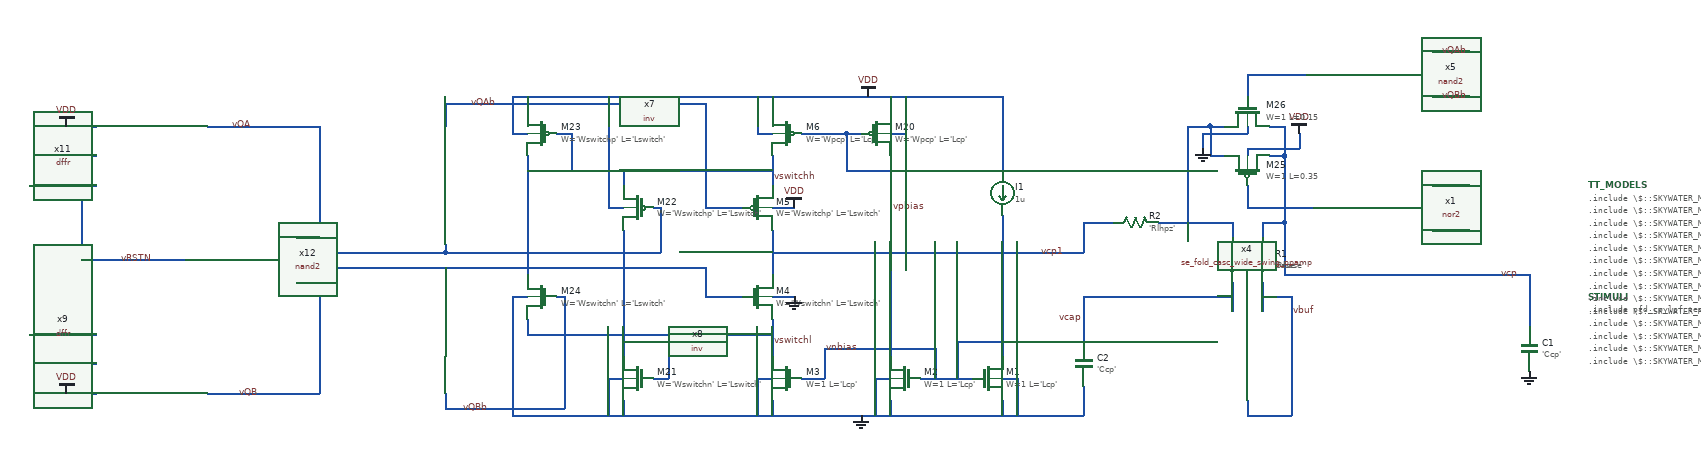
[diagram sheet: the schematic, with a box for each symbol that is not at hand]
v {xschem version=2.9.9 file_version=1.2 }
G {}
K {}
V {}
S {}
E {}
N -160 -350 -70 -350 { lab=vin_div}
N -160 -550 -70 -550 { lab=vsig_in}
N 200 -420 230 -420 { lab=vQB}
N 1000 -260 1000 -240 { lab=GND}
N 980 -290 1000 -290 { lab=GND}
N 980 -290 980 -240 { lab=GND}
N 1000 -620 1020 -620 { lab=VDD}
N 1000 -670 1000 -650 { lab=VDD}
N 1020 -670 1020 -620 { lab=VDD}
N 1040 -290 1110 -290 { lab=vnbias}
N 940 -620 940 -570 { lab=vpbias}
N 940 -570 1000 -570 { lab=vpbias}
N 940 -620 960 -620 { lab=vpbias}
N 1000 -590 1000 -320 { lab=vpbias}
N 1150 -260 1150 -240 { lab=GND}
N 1150 -290 1170 -290 { lab=GND}
N 1170 -290 1170 -240 { lab=GND}
N 880 -620 940 -620 { lab=vpbias}
N 820 -620 840 -620 { lab=VDD}
N 820 -670 820 -620 { lab=VDD}
N 840 -670 840 -650 { lab=VDD}
N 840 -260 840 -240 { lab=GND}
N 820 -290 840 -290 { lab=GND}
N 820 -290 820 -240 { lab=GND}
N 1060 -330 1060 -290 { lab=vnbias}
N 910 -330 1060 -330 { lab=vnbias}
N 910 -330 910 -290 { lab=vnbias}
N 880 -290 910 -290 { lab=vnbias}
N 840 -590 840 -550 { lab=vswitchh}
N 840 -490 840 -430 { lab=vcp1}
N 840 -370 840 -320 { lab=vswitchl}
N 840 -400 870 -400 { lab=GND}
N 840 -520 870 -520 { lab=VDD}
N 1150 -670 1150 -570 { lab=VDD}
N 1150 -510 1150 -320 { lab=vnbias}
N 1090 -340 1090 -290 { lab=vnbias}
N 1090 -340 1150 -340 { lab=vnbias}
N 1480 -240 1540 -240 { lab=vbuf}
N 1480 -260 1480 -240 { lab=vbuf}
N 1260 -280 1260 -240 { lab=GND}
N 1500 -400 1540 -400 { lab=vbuf}
N 1540 -400 1540 -240 { lab=vbuf}
N 1260 -400 1260 -340 { lab=vcap}
N 1460 -420 1460 -380 { lab=vcap}
N 1500 -420 1500 -380 { lab=vbuf}
N 840 -460 1260 -460 { lab=vcp1}
N 1460 -500 1460 -480 { lab=#net1}
N 1500 -500 1500 -480 { lab=vcp}
N 620 -520 640 -520 { lab=VDD}
N 680 -290 700 -290 { lab=#net2}
N 700 -340 700 -290 { lab=#net2}
N 640 -340 700 -340 { lab=#net2}
N 510 -370 510 -350 { lab=vswitchl}
N 490 -400 510 -400 { lab=GND}
N 490 -620 510 -620 { lab=VDD}
N 490 -670 490 -620 { lab=VDD}
N 510 -670 510 -650 { lab=VDD}
N 620 -290 640 -290 { lab=GND}
N 640 -260 640 -240 { lab=GND}
N 620 -290 620 -240 { lab=GND}
N 550 -620 570 -620 { lab=#net3}
N 570 -620 570 -570 { lab=#net3}
N 510 -570 570 -570 { lab=#net3}
N 640 -570 840 -570 { lab=vswitchh}
N 510 -350 840 -350 { lab=vswitchl}
N 780 -520 800 -520 { lab=vQAb}
N 680 -520 690 -520 { lab=vQA}
N 780 -400 800 -400 { lab=vQB}
N 550 -400 560 -400 { lab=vQBb}
N 490 -240 1260 -240 { lab=GND}
N 490 -670 1150 -670 { lab=VDD}
N 750 -520 780 -520 { lab=vQAb}
N 750 -440 750 -400 { lab=vQB}
N 750 -400 780 -400 { lab=vQB}
N 640 -570 640 -550 { lab=vswitchh}
N 640 -490 640 -320 { lab=#net2}
N 620 -670 620 -520 { lab=VDD}
N 490 -400 490 -240 { lab=GND}
N 510 -590 510 -430 { lab=#net3}
N 1260 -400 1290 -400 { lab=vcap}
N 1430 -630 1430 -610 { lab=#net1}
N 1430 -630 1450 -630 { lab=#net1}
N 1430 -610 1430 -590 { lab=#net1}
N 1430 -590 1450 -590 { lab=#net1}
N 1510 -630 1530 -630 { lab=vcp}
N 1530 -630 1530 -590 { lab=vcp}
N 1510 -590 1530 -590 { lab=vcp}
N 1390 -400 1460 -400 { lab=vcap}
N 1480 -550 1480 -520 { lab=#net4}
N 1480 -700 1480 -670 { lab=#net5}
N 1480 -600 1480 -590 { lab=VDD}
N 1480 -630 1480 -620 { lab=GND}
N 1480 -600 1550 -600 { lab=VDD}
N 1550 -620 1550 -600 { lab=VDD}
N 1420 -620 1480 -620 { lab=GND}
N 1420 -620 1420 -600 { lab=GND}
N 1400 -630 1430 -630 { lab=#net1}
N 1290 -400 1390 -400 { lab=vcap}
N 1260 -500 1260 -460 { lab=vcp1}
N 1500 -500 1530 -500 { lab=vcp}
N 1480 -700 1560 -700 { lab=#net5}
N 1730 -730 1780 -730 { lab=vQAb}
N 1730 -670 1780 -670 { lab=vQBb}
N 1730 -550 1780 -550 { lab=vQA}
N 1730 -490 1780 -490 { lab=vQB}
N 1530 -500 1530 -430 { lab=vcp}
N 1530 -430 1860 -430 { lab=vcp}
N 80 -630 230 -630 { lab=vQA}
N 80 -270 230 -270 { lab=vQB}
N -90 -450 50 -450 { lab=vRSTN}
N 400 -660 400 -630 { lab=vQAb}
N 400 -270 400 -250 { lab=vQBb}
N 400 -470 400 -460 { lab=vQA}
N 400 -440 400 -430 { lab=vQB}
N 230 -630 230 -460 { lab=vQA}
N 230 -460 400 -460 { lab=vQA}
N 400 -660 750 -660 { lab=vQAb}
N 750 -660 750 -520 { lab=vQAb}
N 400 -460 690 -460 { lab=vQA}
N 690 -520 690 -460 { lab=vQA}
N 200 -480 230 -480 { lab=vQA}
N 230 -440 230 -420 { lab=vQB}
N 230 -440 750 -440 { lab=vQB}
N 400 -250 560 -250 { lab=vQBb}
N 560 -400 560 -250 { lab=vQBb}
N -90 -310 -70 -310 { lab=vRSTN}
N -90 -590 -90 -310 { lab=vRSTN}
N -90 -590 -70 -590 { lab=vRSTN}
N -110 -630 -70 -630 { lab=VDD}
N -110 -270 -70 -270 { lab=VDD}
N 1860 -430 1860 -360 { lab=vcp}
N 1260 -500 1300 -500 { lab=vcp1}
N 1360 -500 1460 -500 { lab=#net1}
N 1400 -630 1400 -500 { lab=#net1}
N 1530 -590 1530 -500 { lab=vcp}
N 1480 -520 1570 -520 { lab=#net4}
N 230 -420 230 -270 { lab=vQB}
C {devices/title.sym} 160 -30 0 0 {name=l1 author="Nikhil Poole"}
C {devices/code.sym} 1940 -400 0 0 {name=STIMULI 
only_toplevel=true
place=end
value=".include pfd_cp_lpf_test_commands.spice"}
C {devices/code.sym} 1940 -550 0 0 {name=TT_MODELS
only_toplevel=true
format="tcleval( @value )"
value="
.include \\\\$::SKYWATER_MODELS\\\\/cells/nfet_01v8/sky130_fd_pr__nfet_01v8__tt.corner.spice
.include \\\\$::SKYWATER_MODELS\\\\/cells/nfet_01v8_lvt/sky130_fd_pr__nfet_01v8_lvt__tt.corner.spice
.include \\\\$::SKYWATER_MODELS\\\\/cells/pfet_01v8/sky130_fd_pr__pfet_01v8__tt.corner.spice
.include \\\\$::SKYWATER_MODELS\\\\/cells/nfet_03v3_nvt/sky130_fd_pr__nfet_03v3_nvt__tt.corner.spice
.include \\\\$::SKYWATER_MODELS\\\\/cells/nfet_05v0_nvt/sky130_fd_pr__nfet_05v0_nvt__tt.corner.spice
.include \\\\$::SKYWATER_MODELS\\\\/cells/esd_nfet_01v8/sky130_fd_pr__esd_nfet_01v8__tt.corner.spice
.include \\\\$::SKYWATER_MODELS\\\\/cells/pfet_01v8_lvt/sky130_fd_pr__pfet_01v8_lvt__tt.corner.spice
.include \\\\$::SKYWATER_MODELS\\\\/cells/pfet_01v8_hvt/sky130_fd_pr__pfet_01v8_hvt__tt.corner.spice
.include \\\\$::SKYWATER_MODELS\\\\/cells/esd_pfet_g5v0d10v5/sky130_fd_pr__esd_pfet_g5v0d10v5__tt.corner.spice
.include \\\\$::SKYWATER_MODELS\\\\/cells/pfet_g5v0d10v5/sky130_fd_pr__pfet_g5v0d10v5__tt.corner.spice
.include \\\\$::SKYWATER_MODELS\\\\/cells/pfet_g5v0d16v0/sky130_fd_pr__pfet_g5v0d16v0__tt.corner.spice
.include \\\\$::SKYWATER_MODELS\\\\/cells/nfet_g5v0d10v5/sky130_fd_pr__nfet_g5v0d10v5__tt.corner.spice
.include \\\\$::SKYWATER_MODELS\\\\/cells/nfet_g5v0d16v0/sky130_fd_pr__nfet_g5v0d16v0__tt_discrete.corner.spice
.include \\\\$::SKYWATER_MODELS\\\\/cells/esd_nfet_g5v0d10v5/sky130_fd_pr__esd_nfet_g5v0d10v5__tt.corner.spice
.include \\\\$::SKYWATER_MODELS\\\\/models/corners/tt/nonfet.spice
* Mismatch parameters
.include \\\\$::SKYWATER_MODELS\\\\/cells/nfet_01v8/sky130_fd_pr__nfet_01v8__mismatch.corner.spice
.include \\\\$::SKYWATER_MODELS\\\\/cells/pfet_01v8/sky130_fd_pr__pfet_01v8__mismatch.corner.spice
.include \\\\$::SKYWATER_MODELS\\\\/cells/nfet_01v8_lvt/sky130_fd_pr__nfet_01v8_lvt__mismatch.corner.spice
.include \\\\$::SKYWATER_MODELS\\\\/cells/pfet_01v8_lvt/sky130_fd_pr__pfet_01v8_lvt__mismatch.corner.spice
.include \\\\$::SKYWATER_MODELS\\\\/cells/pfet_01v8_hvt/sky130_fd_pr__pfet_01v8_hvt__mismatch.corner.spice
.include \\\\$::SKYWATER_MODELS\\\\/cells/nfet_g5v0d10v5/sky130_fd_pr__nfet_g5v0d10v5__mismatch.corner.spice
.include \\\\$::SKYWATER_MODELS\\\\/cells/pfet_g5v0d10v5/sky130_fd_pr__pfet_g5v0d10v5__mismatch.corner.spice
.include \\\\$::SKYWATER_MODELS\\\\/cells/nfet_05v0_nvt/sky130_fd_pr__nfet_05v0_nvt__mismatch.corner.spice
.include \\\\$::SKYWATER_MODELS\\\\/cells/nfet_03v3_nvt/sky130_fd_pr__nfet_03v3_nvt__mismatch.corner.spice
* Resistor\\\\$::SKYWATER_MODELS\\\\/Capacitor
.include \\\\$::SKYWATER_MODELS\\\\/models/r+c/res_typical__cap_typical.spice
.include \\\\$::SKYWATER_MODELS\\\\/models/r+c/res_typical__cap_typical__lin.spice
* Special cells
.include \\\\$::SKYWATER_MODELS\\\\/models/corners/tt/specialized_cells.spice
* All models
.include \\\\$::SKYWATER_MODELS\\\\/models/all.spice
* Corner
.include \\\\$::SKYWATER_MODELS\\\\/models/corners/tt/rf.spice
"}
C {devices/lab_wire.sym} -100 -550 0 0 {name=l2 sig_type=std_logic lab=vsig_in}
C {devices/lab_wire.sym} -100 -350 0 0 {name=l3 sig_type=std_logic lab=vin_div}
C {devices/lab_wire.sym} 910 -330 0 1 {name=l5 sig_type=std_logic lab=vnbias}
C {devices/lab_wire.sym} 1000 -520 0 1 {name=l6 sig_type=std_logic lab=vpbias}
C {devices/isource.sym} 1150 -540 0 1 {name=I1 value=1u}
C {sky130_fd_pr/nfet_01v8.sym} 1130 -290 0 0 {name=M1
L='Lcp'
W=1
nf=1 
mult=100
ad="'int((nf+1)/2) * W/nf * 0.29'" 
pd="'2*int((nf+1)/2) * (W/nf + 0.29)'"
as="'int((nf+2)/2) * W/nf * 0.29'" 
ps="'2*int((nf+2)/2) * (W/nf + 0.29)'"
nrd="'0.29 / W'" nrs="'0.29 / W'"
sa=0 sb=0 sd=0
model=nfet_01v8
spiceprefix=X
}
C {sky130_fd_pr/nfet_01v8.sym} 1020 -290 0 1 {name=M2
L='Lcp'
W=1
nf=1 
mult=1
ad="'int((nf+1)/2) * W/nf * 0.29'" 
pd="'2*int((nf+1)/2) * (W/nf + 0.29)'"
as="'int((nf+2)/2) * W/nf * 0.29'" 
ps="'2*int((nf+2)/2) * (W/nf + 0.29)'"
nrd="'0.29 / W'" nrs="'0.29 / W'"
sa=0 sb=0 sd=0
model=nfet_01v8
spiceprefix=X
}
C {sky130_fd_pr/nfet_01v8.sym} 860 -290 0 1 {name=M3
L='Lcp'
W=1
nf=1 
mult=1
ad="'int((nf+1)/2) * W/nf * 0.29'" 
pd="'2*int((nf+1)/2) * (W/nf + 0.29)'"
as="'int((nf+2)/2) * W/nf * 0.29'" 
ps="'2*int((nf+2)/2) * (W/nf + 0.29)'"
nrd="'0.29 / W'" nrs="'0.29 / W'"
sa=0 sb=0 sd=0
model=nfet_01v8
spiceprefix=X
}
C {sky130_fd_pr/nfet_01v8_lvt.sym} 820 -400 0 0 {name=M4
L='Lswitch'
W='Wswitchn'
nf=1
mult=1
ad="'int((nf+1)/2) * W/nf * 0.29'" 
pd="'2*int((nf+1)/2) * (W/nf + 0.29)'"
as="'int((nf+2)/2) * W/nf * 0.29'" 
ps="'2*int((nf+2)/2) * (W/nf + 0.29)'"
nrd="'0.29 / W'" nrs="'0.29 / W'"
sa=0 sb=0 sd=0
model=nfet_01v8_lvt
spiceprefix=X
}
C {sky130_fd_pr/pfet_01v8_lvt.sym} 820 -520 0 0 {name=M5
L='Lswitch'
W='Wswitchp'
nf=1
mult=1
ad="'int((nf+1)/2) * W/nf * 0.29'" 
pd="'2*int((nf+1)/2) * (W/nf + 0.29)'"
as="'int((nf+2)/2) * W/nf * 0.29'" 
ps="'2*int((nf+2)/2) * (W/nf + 0.29)'"
nrd="'0.29 / W'" nrs="'0.29 / W'"
sa=0 sb=0 sd=0
model=pfet_01v8_lvt
spiceprefix=X
}
C {devices/gnd.sym} 870 -400 0 0 {name=l7 lab=GND}
C {devices/gnd.sym} 960 -240 0 0 {name=l8 lab=GND}
C {devices/vdd.sym} 970 -670 0 0 {name=l9 lab=VDD}
C {devices/vdd.sym} 870 -520 0 0 {name=l10 lab=VDD}
C {devices/lab_wire.sym} 1820 -430 0 1 {name=l12 sig_type=std_logic lab=vcp}
C {sky130_fd_pr/pfet_01v8.sym} 860 -620 0 1 {name=M6
L='Lcp'
W='Wpcp'
nf=1
mult='Mpcp'
ad="'int((nf+1)/2) * W/nf * 0.29'" 
pd="'2*int((nf+1)/2) * (W/nf + 0.29)'"
as="'int((nf+2)/2) * W/nf * 0.29'" 
ps="'2*int((nf+2)/2) * (W/nf + 0.29)'"
nrd="'0.29 / W'" nrs="'0.29 / W'"
sa=0 sb=0 sd=0
model=pfet_01v8
spiceprefix=X
}
C {sky130_fd_pr/pfet_01v8.sym} 980 -620 0 0 {name=M20
L='Lcp'
W='Wpcp'
nf=1
mult='Mpcp'
ad="'int((nf+1)/2) * W/nf * 0.29'" 
pd="'2*int((nf+1)/2) * (W/nf + 0.29)'"
as="'int((nf+2)/2) * W/nf * 0.29'" 
ps="'2*int((nf+2)/2) * (W/nf + 0.29)'"
nrd="'0.29 / W'" nrs="'0.29 / W'"
sa=0 sb=0 sd=0
model=pfet_01v8
spiceprefix=X
}
C {devices/capa.sym} 1260 -310 0 0 {name=C2
m=1
value='Ccp'
footprint=1206
device="ceramic capacitor"}
C {devices/res.sym} 1500 -450 0 0 {name=R1
value='Rbase'
footprint=1206
device=resistor
m=1}
C {devices/res.sym} 1460 -450 0 1 {name=R4
value='Kcap*Rbase'
footprint=1206
device=resistor
m=1}
C {devices/lab_wire.sym} 1260 -370 0 0 {name=l35 sig_type=std_logic lab=vcap}
C {devices/lab_wire.sym} 1540 -380 2 0 {name=l36 sig_type=std_logic lab=vbuf}
C {/home/users/nhpoole/ee272b/ee272b_mixed_signal_mmwave_accelerator/designs/se_fold_casc_wide_swing_opamp.sym} 1480 -330 3 1 {name=x4}
C {devices/lab_wire.sym} 150 -270 0 0 {name=l37 sig_type=std_logic lab=vQB}
C {devices/lab_wire.sym} 840 -560 0 1 {name=l38 sig_type=std_logic lab=vswitchh}
C {devices/lab_wire.sym} 840 -340 0 1 {name=l39 sig_type=std_logic lab=vswitchl}
C {sky130_fd_pr/nfet_01v8.sym} 660 -290 0 1 {name=M21
L='Lswitch'
W='Wswitchn'
nf=1 
mult=1
ad="'int((nf+1)/2) * W/nf * 0.29'" 
pd="'2*int((nf+1)/2) * (W/nf + 0.29)'"
as="'int((nf+2)/2) * W/nf * 0.29'" 
ps="'2*int((nf+2)/2) * (W/nf + 0.29)'"
nrd="'0.29 / W'" nrs="'0.29 / W'"
sa=0 sb=0 sd=0
model=nfet_01v8
spiceprefix=X
}
C {sky130_fd_pr/pfet_01v8.sym} 660 -520 0 1 {name=M22
L='Lswitch'
W='Wswitchp'
nf=1
mult=1
ad="'int((nf+1)/2) * W/nf * 0.29'" 
pd="'2*int((nf+1)/2) * (W/nf + 0.29)'"
as="'int((nf+2)/2) * W/nf * 0.29'" 
ps="'2*int((nf+2)/2) * (W/nf + 0.29)'"
nrd="'0.29 / W'" nrs="'0.29 / W'"
sa=0 sb=0 sd=0
model=pfet_01v8
spiceprefix=X
}
C {devices/lab_wire.sym} 110 -630 0 1 {name=l40 sig_type=std_logic lab=vQA}
C {sky130_fd_pr/pfet_01v8.sym} 530 -620 0 1 {name=M23
L='Lswitch'
W='Wswitchp'
nf=1
mult=1
ad="'int((nf+1)/2) * W/nf * 0.29'" 
pd="'2*int((nf+1)/2) * (W/nf + 0.29)'"
as="'int((nf+2)/2) * W/nf * 0.29'" 
ps="'2*int((nf+2)/2) * (W/nf + 0.29)'"
nrd="'0.29 / W'" nrs="'0.29 / W'"
sa=0 sb=0 sd=0
model=pfet_01v8
spiceprefix=X
}
C {sky130_fd_pr/nfet_01v8.sym} 530 -400 0 1 {name=M24
L='Lswitch'
W='Wswitchn'
nf=1 
mult=1
ad="'int((nf+1)/2) * W/nf * 0.29'" 
pd="'2*int((nf+1)/2) * (W/nf + 0.29)'"
as="'int((nf+2)/2) * W/nf * 0.29'" 
ps="'2*int((nf+2)/2) * (W/nf + 0.29)'"
nrd="'0.29 / W'" nrs="'0.29 / W'"
sa=0 sb=0 sd=0
model=nfet_01v8
spiceprefix=X
}
C {devices/lab_wire.sym} 460 -250 0 0 {name=l41 sig_type=std_logic lab=vQBb}
C {devices/vdd.sym} 1550 -620 0 0 {name=l42 lab=VDD}
C {devices/gnd.sym} 1420 -600 0 0 {name=l43 lab=GND}
C {sky130_fd_pr/pfet_01v8_lvt.sym} 1480 -570 3 0 {name=M25
L=0.35
W=1
nf=1
mult=1
ad="'int((nf+1)/2) * W/nf * 0.29'" 
pd="'2*int((nf+1)/2) * (W/nf + 0.29)'"
as="'int((nf+2)/2) * W/nf * 0.29'" 
ps="'2*int((nf+2)/2) * (W/nf + 0.29)'"
nrd="'0.29 / W'" nrs="'0.29 / W'"
sa=0 sb=0 sd=0
model=pfet_01v8_lvt
spiceprefix=X
}
C {sky130_fd_pr/nfet_01v8_lvt.sym} 1480 -650 1 0 {name=M26
L=0.15
W=1
nf=1
mult=1
ad="'int((nf+1)/2) * W/nf * 0.29'" 
pd="'2*int((nf+1)/2) * (W/nf + 0.29)'"
as="'int((nf+2)/2) * W/nf * 0.29'" 
ps="'2*int((nf+2)/2) * (W/nf + 0.29)'"
nrd="'0.29 / W'" nrs="'0.29 / W'"
sa=0 sb=0 sd=0
model=nfet_01v8_lvt
spiceprefix=X
}
C {devices/lab_wire.sym} 1200 -460 0 1 {name=l44 sig_type=std_logic lab=vcp1}
C {/home/users/nhpoole/ee272b/ee272b_mixed_signal_mmwave_accelerator/designs/nand2.sym} 1660 -700 0 1 {name=x5 M=1}
C {devices/lab_wire.sym} 1740 -730 0 1 {name=l45 sig_type=std_logic lab=vQAb}
C {devices/lab_wire.sym} 1740 -550 0 1 {name=l46 sig_type=std_logic lab=vQA}
C {devices/lab_wire.sym} 1740 -490 0 1 {name=l47 sig_type=std_logic lab=vQB}
C {devices/lab_wire.sym} 1740 -670 0 1 {name=l48 sig_type=std_logic lab=vQBb}
C {devices/lab_wire.sym} -40 -450 0 1 {name=l49 sig_type=std_logic lab=vRSTN}
C {/home/users/nhpoole/ee272b/ee272b_mixed_signal_mmwave_accelerator/designs/inv.sym} 400 -520 3 0 {name=x7 M=1}
C {/home/users/nhpoole/ee272b/ee272b_mixed_signal_mmwave_accelerator/designs/inv.sym} 400 -380 1 0 {name=x8 M=1}
C {devices/lab_wire.sym} 470 -660 0 0 {name=l50 sig_type=std_logic lab=vQAb}
C {/home/users/nhpoole/ee272b/ee272b_mixed_signal_mmwave_accelerator/designs/dffr.sym} 0 -310 2 1 {name=x9 M=1}
C {/home/users/nhpoole/ee272b/ee272b_mixed_signal_mmwave_accelerator/designs/dffr.sym} 0 -590 0 0 {name=x11 M=1}
C {devices/vdd.sym} -110 -630 0 0 {name=l51 lab=VDD}
C {devices/vdd.sym} -110 -270 2 1 {name=l52 lab=VDD}
C {/home/users/nhpoole/ee272b/ee272b_mixed_signal_mmwave_accelerator/designs/nand2.sym} 130 -450 0 1 {name=x12 M=1}
C {devices/capa.sym} 1860 -330 0 0 {name=C1
m=1
value='Ccp'
footprint=1206
device="ceramic capacitor"}
C {devices/gnd.sym} 1860 -300 0 0 {name=l4 lab=GND}
C {devices/res.sym} 1330 -500 1 1 {name=R2
value='Rlhpz'
footprint=1206
device=resistor
m=1}
C {/home/users/nhpoole/ee272b/ee272b_mixed_signal_mmwave_accelerator/designs/nor2.sym} 1680 -520 0 1 {name=x1 M=1}
C {devices/noconn.sym} 80 -350 0 1 {name=l11}
C {devices/noconn.sym} 80 -550 0 1 {name=l13}
